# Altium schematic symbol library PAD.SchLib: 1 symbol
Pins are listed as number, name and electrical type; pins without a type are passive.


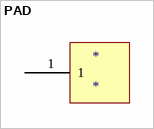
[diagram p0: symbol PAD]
## PAD
designator *
pins: 1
